VERSION 5.7 ;
  NOWIREEXTENSIONATPIN ON ;
  DIVIDERCHAR "/" ;
  BUSBITCHARS "[]" ;
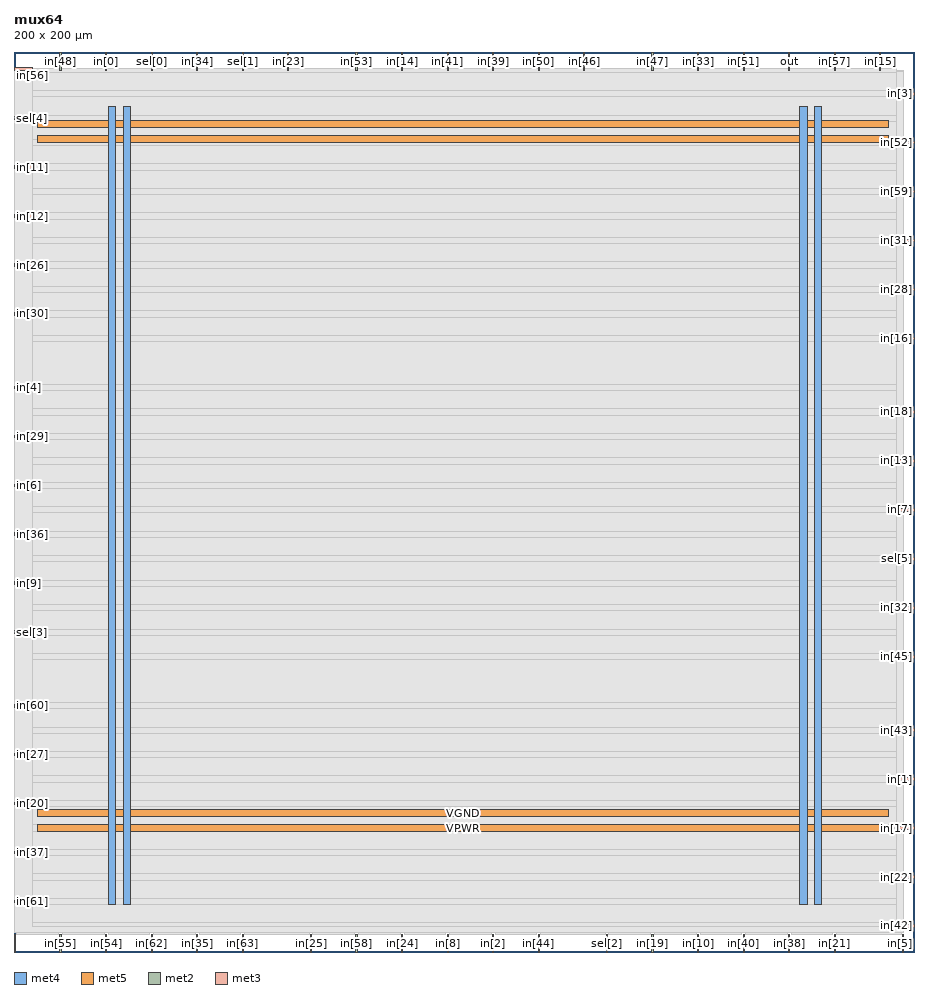
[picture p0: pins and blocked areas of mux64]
MACRO mux64
  CLASS BLOCK ;
  FOREIGN mux64 ;
  ORIGIN 0.000 0.000 ;
  SIZE 200.000 BY 200.000 ;
  PIN VGND
    DIRECTION INOUT ;
    USE GROUND ;
    PORT
      LAYER met4 ;
        RECT 24.340 10.640 25.940 187.920 ;
    END
    PORT
      LAYER met4 ;
        RECT 177.940 10.640 179.540 187.920 ;
    END
    PORT
      LAYER met5 ;
        RECT 5.280 30.030 194.360 31.630 ;
    END
    PORT
      LAYER met5 ;
        RECT 5.280 183.210 194.360 184.810 ;
    END
  END VGND
  PIN VPWR
    DIRECTION INOUT ;
    USE POWER ;
    PORT
      LAYER met4 ;
        RECT 21.040 10.640 22.640 187.920 ;
    END
    PORT
      LAYER met4 ;
        RECT 174.640 10.640 176.240 187.920 ;
    END
    PORT
      LAYER met5 ;
        RECT 5.280 26.730 194.360 28.330 ;
    END
    PORT
      LAYER met5 ;
        RECT 5.280 179.910 194.360 181.510 ;
    END
  END VPWR
  PIN in[0]
    DIRECTION INPUT ;
    USE SIGNAL ;
    ANTENNAGATEAREA 0.126000 ;
    PORT
      LAYER met2 ;
        RECT 20.330 196.000 20.610 200.000 ;
    END
  END in[0]
  PIN in[10]
    DIRECTION INPUT ;
    USE SIGNAL ;
    ANTENNAGATEAREA 0.196500 ;
    PORT
      LAYER met2 ;
        RECT 151.890 0.000 152.170 4.000 ;
    END
  END in[10]
  PIN in[11]
    DIRECTION INPUT ;
    USE SIGNAL ;
    ANTENNAGATEAREA 0.126000 ;
    PORT
      LAYER met3 ;
        RECT 0.000 174.120 4.000 174.720 ;
    END
  END in[11]
  PIN in[12]
    DIRECTION INPUT ;
    USE SIGNAL ;
    ANTENNAGATEAREA 0.196500 ;
    PORT
      LAYER met3 ;
        RECT 0.000 163.240 4.000 163.840 ;
    END
  END in[12]
  PIN in[13]
    DIRECTION INPUT ;
    USE SIGNAL ;
    ANTENNAGATEAREA 0.196500 ;
    PORT
      LAYER met3 ;
        RECT 196.000 108.840 200.000 109.440 ;
    END
  END in[13]
  PIN in[14]
    DIRECTION INPUT ;
    USE SIGNAL ;
    ANTENNAGATEAREA 0.196500 ;
    PORT
      LAYER met2 ;
        RECT 86.110 196.000 86.390 200.000 ;
    END
  END in[14]
  PIN in[15]
    DIRECTION INPUT ;
    USE SIGNAL ;
    ANTENNAGATEAREA 0.196500 ;
    PORT
      LAYER met2 ;
        RECT 192.370 196.000 192.650 200.000 ;
    END
  END in[15]
  PIN in[16]
    DIRECTION INPUT ;
    USE SIGNAL ;
    ANTENNAGATEAREA 0.196500 ;
    PORT
      LAYER met3 ;
        RECT 196.000 136.040 200.000 136.640 ;
    END
  END in[16]
  PIN in[17]
    DIRECTION INPUT ;
    USE SIGNAL ;
    ANTENNAGATEAREA 0.196500 ;
    PORT
      LAYER met3 ;
        RECT 196.000 27.240 200.000 27.840 ;
    END
  END in[17]
  PIN in[18]
    DIRECTION INPUT ;
    USE SIGNAL ;
    ANTENNAGATEAREA 0.196500 ;
    PORT
      LAYER met3 ;
        RECT 196.000 119.720 200.000 120.320 ;
    END
  END in[18]
  PIN in[19]
    DIRECTION INPUT ;
    USE SIGNAL ;
    ANTENNAGATEAREA 0.196500 ;
    PORT
      LAYER met2 ;
        RECT 141.770 0.000 142.050 4.000 ;
    END
  END in[19]
  PIN in[1]
    DIRECTION INPUT ;
    USE SIGNAL ;
    ANTENNAGATEAREA 0.196500 ;
    PORT
      LAYER met3 ;
        RECT 196.000 38.120 200.000 38.720 ;
    END
  END in[1]
  PIN in[20]
    DIRECTION INPUT ;
    USE SIGNAL ;
    ANTENNAGATEAREA 0.196500 ;
    PORT
      LAYER met3 ;
        RECT 0.000 32.680 4.000 33.280 ;
    END
  END in[20]
  PIN in[21]
    DIRECTION INPUT ;
    USE SIGNAL ;
    ANTENNAGATEAREA 0.196500 ;
    PORT
      LAYER met2 ;
        RECT 182.250 0.000 182.530 4.000 ;
    END
  END in[21]
  PIN in[22]
    DIRECTION INPUT ;
    USE SIGNAL ;
    ANTENNAGATEAREA 0.196500 ;
    PORT
      LAYER met3 ;
        RECT 196.000 16.360 200.000 16.960 ;
    END
  END in[22]
  PIN in[23]
    DIRECTION INPUT ;
    USE SIGNAL ;
    ANTENNAGATEAREA 0.126000 ;
    PORT
      LAYER met2 ;
        RECT 60.810 196.000 61.090 200.000 ;
    END
  END in[23]
  PIN in[24]
    DIRECTION INPUT ;
    USE SIGNAL ;
    ANTENNAGATEAREA 0.196500 ;
    PORT
      LAYER met2 ;
        RECT 86.110 0.000 86.390 4.000 ;
    END
  END in[24]
  PIN in[25]
    DIRECTION INPUT ;
    USE SIGNAL ;
    ANTENNAGATEAREA 0.196500 ;
    PORT
      LAYER met2 ;
        RECT 65.870 0.000 66.150 4.000 ;
    END
  END in[25]
  PIN in[26]
    DIRECTION INPUT ;
    USE SIGNAL ;
    ANTENNAGATEAREA 0.196500 ;
    PORT
      LAYER met3 ;
        RECT 0.000 152.360 4.000 152.960 ;
    END
  END in[26]
  PIN in[27]
    DIRECTION INPUT ;
    USE SIGNAL ;
    ANTENNAGATEAREA 0.196500 ;
    PORT
      LAYER met3 ;
        RECT 0.000 43.560 4.000 44.160 ;
    END
  END in[27]
  PIN in[28]
    DIRECTION INPUT ;
    USE SIGNAL ;
    ANTENNAGATEAREA 0.196500 ;
    PORT
      LAYER met3 ;
        RECT 196.000 146.920 200.000 147.520 ;
    END
  END in[28]
  PIN in[29]
    DIRECTION INPUT ;
    USE SIGNAL ;
    ANTENNAGATEAREA 0.196500 ;
    PORT
      LAYER met3 ;
        RECT 0.000 114.280 4.000 114.880 ;
    END
  END in[29]
  PIN in[2]
    DIRECTION INPUT ;
    USE SIGNAL ;
    ANTENNAGATEAREA 0.196500 ;
    PORT
      LAYER met2 ;
        RECT 106.350 0.000 106.630 4.000 ;
    END
  END in[2]
  PIN in[30]
    DIRECTION INPUT ;
    USE SIGNAL ;
    ANTENNAGATEAREA 0.196500 ;
    PORT
      LAYER met3 ;
        RECT 0.000 141.480 4.000 142.080 ;
    END
  END in[30]
  PIN in[31]
    DIRECTION INPUT ;
    USE SIGNAL ;
    ANTENNAGATEAREA 0.126000 ;
    PORT
      LAYER met3 ;
        RECT 196.000 157.800 200.000 158.400 ;
    END
  END in[31]
  PIN in[32]
    DIRECTION INPUT ;
    USE SIGNAL ;
    ANTENNAGATEAREA 0.196500 ;
    PORT
      LAYER met3 ;
        RECT 196.000 76.200 200.000 76.800 ;
    END
  END in[32]
  PIN in[33]
    DIRECTION INPUT ;
    USE SIGNAL ;
    ANTENNAGATEAREA 0.196500 ;
    PORT
      LAYER met2 ;
        RECT 151.890 196.000 152.170 200.000 ;
    END
  END in[33]
  PIN in[34]
    DIRECTION INPUT ;
    USE SIGNAL ;
    ANTENNAGATEAREA 0.196500 ;
    PORT
      LAYER met2 ;
        RECT 40.570 196.000 40.850 200.000 ;
    END
  END in[34]
  PIN in[35]
    DIRECTION INPUT ;
    USE SIGNAL ;
    ANTENNAGATEAREA 0.196500 ;
    PORT
      LAYER met2 ;
        RECT 40.570 0.000 40.850 4.000 ;
    END
  END in[35]
  PIN in[36]
    DIRECTION INPUT ;
    USE SIGNAL ;
    ANTENNAGATEAREA 0.196500 ;
    PORT
      LAYER met3 ;
        RECT 0.000 92.520 4.000 93.120 ;
    END
  END in[36]
  PIN in[37]
    DIRECTION INPUT ;
    USE SIGNAL ;
    ANTENNAGATEAREA 0.196500 ;
    PORT
      LAYER met3 ;
        RECT 0.000 21.800 4.000 22.400 ;
    END
  END in[37]
  PIN in[38]
    DIRECTION INPUT ;
    USE SIGNAL ;
    ANTENNAGATEAREA 0.196500 ;
    PORT
      LAYER met2 ;
        RECT 172.130 0.000 172.410 4.000 ;
    END
  END in[38]
  PIN in[39]
    DIRECTION INPUT ;
    USE SIGNAL ;
    ANTENNAGATEAREA 0.196500 ;
    PORT
      LAYER met2 ;
        RECT 106.350 196.000 106.630 200.000 ;
    END
  END in[39]
  PIN in[3]
    DIRECTION INPUT ;
    USE SIGNAL ;
    ANTENNAGATEAREA 0.196500 ;
    PORT
      LAYER met3 ;
        RECT 196.000 190.440 200.000 191.040 ;
    END
  END in[3]
  PIN in[40]
    DIRECTION INPUT ;
    USE SIGNAL ;
    ANTENNAGATEAREA 0.196500 ;
    PORT
      LAYER met2 ;
        RECT 162.010 0.000 162.290 4.000 ;
    END
  END in[40]
  PIN in[41]
    DIRECTION INPUT ;
    USE SIGNAL ;
    ANTENNAGATEAREA 0.196500 ;
    PORT
      LAYER met2 ;
        RECT 96.230 196.000 96.510 200.000 ;
    END
  END in[41]
  PIN in[42]
    DIRECTION INPUT ;
    USE SIGNAL ;
    ANTENNAGATEAREA 0.196500 ;
    PORT
      LAYER met3 ;
        RECT 196.000 5.480 200.000 6.080 ;
    END
  END in[42]
  PIN in[43]
    DIRECTION INPUT ;
    USE SIGNAL ;
    ANTENNAGATEAREA 0.196500 ;
    PORT
      LAYER met3 ;
        RECT 196.000 49.000 200.000 49.600 ;
    END
  END in[43]
  PIN in[44]
    DIRECTION INPUT ;
    USE SIGNAL ;
    ANTENNAGATEAREA 0.196500 ;
    PORT
      LAYER met2 ;
        RECT 116.470 0.000 116.750 4.000 ;
    END
  END in[44]
  PIN in[45]
    DIRECTION INPUT ;
    USE SIGNAL ;
    ANTENNAGATEAREA 0.196500 ;
    PORT
      LAYER met3 ;
        RECT 196.000 65.320 200.000 65.920 ;
    END
  END in[45]
  PIN in[46]
    DIRECTION INPUT ;
    USE SIGNAL ;
    ANTENNAGATEAREA 0.196500 ;
    PORT
      LAYER met2 ;
        RECT 126.590 196.000 126.870 200.000 ;
    END
  END in[46]
  PIN in[47]
    DIRECTION INPUT ;
    USE SIGNAL ;
    ANTENNAGATEAREA 0.196500 ;
    PORT
      LAYER met2 ;
        RECT 141.770 196.000 142.050 200.000 ;
    END
  END in[47]
  PIN in[48]
    DIRECTION INPUT ;
    USE SIGNAL ;
    ANTENNAGATEAREA 0.196500 ;
    PORT
      LAYER met2 ;
        RECT 10.210 196.000 10.490 200.000 ;
    END
  END in[48]
  PIN in[49]
    DIRECTION INPUT ;
    USE SIGNAL ;
    ANTENNAGATEAREA 0.196500 ;
    PORT
      LAYER met2 ;
        RECT 0.090 0.000 0.370 4.000 ;
    END
  END in[49]
  PIN in[4]
    DIRECTION INPUT ;
    USE SIGNAL ;
    ANTENNAGATEAREA 0.196500 ;
    PORT
      LAYER met3 ;
        RECT 0.000 125.160 4.000 125.760 ;
    END
  END in[4]
  PIN in[50]
    DIRECTION INPUT ;
    USE SIGNAL ;
    ANTENNAGATEAREA 0.196500 ;
    PORT
      LAYER met2 ;
        RECT 116.470 196.000 116.750 200.000 ;
    END
  END in[50]
  PIN in[51]
    DIRECTION INPUT ;
    USE SIGNAL ;
    ANTENNAGATEAREA 0.196500 ;
    PORT
      LAYER met2 ;
        RECT 162.010 196.000 162.290 200.000 ;
    END
  END in[51]
  PIN in[52]
    DIRECTION INPUT ;
    USE SIGNAL ;
    ANTENNAGATEAREA 0.196500 ;
    PORT
      LAYER met3 ;
        RECT 196.000 179.560 200.000 180.160 ;
    END
  END in[52]
  PIN in[53]
    DIRECTION INPUT ;
    USE SIGNAL ;
    ANTENNAGATEAREA 0.196500 ;
    PORT
      LAYER met2 ;
        RECT 75.990 196.000 76.270 200.000 ;
    END
  END in[53]
  PIN in[54]
    DIRECTION INPUT ;
    USE SIGNAL ;
    ANTENNAGATEAREA 0.196500 ;
    PORT
      LAYER met2 ;
        RECT 20.330 0.000 20.610 4.000 ;
    END
  END in[54]
  PIN in[55]
    DIRECTION INPUT ;
    USE SIGNAL ;
    ANTENNAGATEAREA 0.196500 ;
    PORT
      LAYER met2 ;
        RECT 10.210 0.000 10.490 4.000 ;
    END
  END in[55]
  PIN in[56]
    DIRECTION INPUT ;
    USE SIGNAL ;
    ANTENNAGATEAREA 0.196500 ;
    PORT
      LAYER met3 ;
        RECT 0.000 195.880 4.000 196.480 ;
    END
  END in[56]
  PIN in[57]
    DIRECTION INPUT ;
    USE SIGNAL ;
    ANTENNAGATEAREA 0.196500 ;
    PORT
      LAYER met2 ;
        RECT 182.250 196.000 182.530 200.000 ;
    END
  END in[57]
  PIN in[58]
    DIRECTION INPUT ;
    USE SIGNAL ;
    ANTENNAGATEAREA 0.196500 ;
    PORT
      LAYER met2 ;
        RECT 75.990 0.000 76.270 4.000 ;
    END
  END in[58]
  PIN in[59]
    DIRECTION INPUT ;
    USE SIGNAL ;
    ANTENNAGATEAREA 0.126000 ;
    PORT
      LAYER met3 ;
        RECT 196.000 168.680 200.000 169.280 ;
    END
  END in[59]
  PIN in[5]
    DIRECTION INPUT ;
    USE SIGNAL ;
    ANTENNAGATEAREA 0.126000 ;
    PORT
      LAYER met2 ;
        RECT 197.430 0.000 197.710 4.000 ;
    END
  END in[5]
  PIN in[60]
    DIRECTION INPUT ;
    USE SIGNAL ;
    ANTENNAGATEAREA 0.196500 ;
    PORT
      LAYER met3 ;
        RECT 0.000 54.440 4.000 55.040 ;
    END
  END in[60]
  PIN in[61]
    DIRECTION INPUT ;
    USE SIGNAL ;
    ANTENNAGATEAREA 0.196500 ;
    PORT
      LAYER met3 ;
        RECT 0.000 10.920 4.000 11.520 ;
    END
  END in[61]
  PIN in[62]
    DIRECTION INPUT ;
    USE SIGNAL ;
    ANTENNAGATEAREA 0.196500 ;
    PORT
      LAYER met2 ;
        RECT 30.450 0.000 30.730 4.000 ;
    END
  END in[62]
  PIN in[63]
    DIRECTION INPUT ;
    USE SIGNAL ;
    ANTENNAGATEAREA 0.196500 ;
    PORT
      LAYER met2 ;
        RECT 50.690 0.000 50.970 4.000 ;
    END
  END in[63]
  PIN in[6]
    DIRECTION INPUT ;
    USE SIGNAL ;
    ANTENNAGATEAREA 0.196500 ;
    PORT
      LAYER met3 ;
        RECT 0.000 103.400 4.000 104.000 ;
    END
  END in[6]
  PIN in[7]
    DIRECTION INPUT ;
    USE SIGNAL ;
    ANTENNAGATEAREA 0.196500 ;
    PORT
      LAYER met3 ;
        RECT 196.000 97.960 200.000 98.560 ;
    END
  END in[7]
  PIN in[8]
    DIRECTION INPUT ;
    USE SIGNAL ;
    ANTENNAGATEAREA 0.196500 ;
    PORT
      LAYER met2 ;
        RECT 96.230 0.000 96.510 4.000 ;
    END
  END in[8]
  PIN in[9]
    DIRECTION INPUT ;
    USE SIGNAL ;
    ANTENNAGATEAREA 0.196500 ;
    PORT
      LAYER met3 ;
        RECT 0.000 81.640 4.000 82.240 ;
    END
  END in[9]
  PIN out
    DIRECTION OUTPUT TRISTATE ;
    USE SIGNAL ;
    ANTENNADIFFAREA 0.795200 ;
    PORT
      LAYER met2 ;
        RECT 172.130 196.000 172.410 200.000 ;
    END
  END out
  PIN sel[0]
    DIRECTION INPUT ;
    USE SIGNAL ;
    ANTENNAGATEAREA 0.159000 ;
    PORT
      LAYER met2 ;
        RECT 30.450 196.000 30.730 200.000 ;
    END
  END sel[0]
  PIN sel[1]
    DIRECTION INPUT ;
    USE SIGNAL ;
    ANTENNAGATEAREA 0.247500 ;
    PORT
      LAYER met2 ;
        RECT 50.690 196.000 50.970 200.000 ;
    END
  END sel[1]
  PIN sel[2]
    DIRECTION INPUT ;
    USE SIGNAL ;
    ANTENNAGATEAREA 0.213000 ;
    PORT
      LAYER met2 ;
        RECT 131.650 0.000 131.930 4.000 ;
    END
  END sel[2]
  PIN sel[3]
    DIRECTION INPUT ;
    USE SIGNAL ;
    ANTENNAGATEAREA 0.159000 ;
    PORT
      LAYER met3 ;
        RECT 0.000 70.760 4.000 71.360 ;
    END
  END sel[3]
  PIN sel[4]
    DIRECTION INPUT ;
    USE SIGNAL ;
    ANTENNAGATEAREA 0.159000 ;
    PORT
      LAYER met3 ;
        RECT 0.000 185.000 4.000 185.600 ;
    END
  END sel[4]
  PIN sel[5]
    DIRECTION INPUT ;
    USE SIGNAL ;
    ANTENNAGATEAREA 0.213000 ;
    PORT
      LAYER met3 ;
        RECT 196.000 87.080 200.000 87.680 ;
    END
  END sel[5]
  OBS
      LAYER li1 ;
        RECT 5.520 10.795 194.120 187.765 ;
      LAYER met1 ;
        RECT 0.070 9.560 197.730 187.920 ;
      LAYER met2 ;
        RECT 0.100 195.720 9.930 196.000 ;
        RECT 10.770 195.720 20.050 196.000 ;
        RECT 20.890 195.720 30.170 196.000 ;
        RECT 31.010 195.720 40.290 196.000 ;
        RECT 41.130 195.720 50.410 196.000 ;
        RECT 51.250 195.720 60.530 196.000 ;
        RECT 61.370 195.720 75.710 196.000 ;
        RECT 76.550 195.720 85.830 196.000 ;
        RECT 86.670 195.720 95.950 196.000 ;
        RECT 96.790 195.720 106.070 196.000 ;
        RECT 106.910 195.720 116.190 196.000 ;
        RECT 117.030 195.720 126.310 196.000 ;
        RECT 127.150 195.720 141.490 196.000 ;
        RECT 142.330 195.720 151.610 196.000 ;
        RECT 152.450 195.720 161.730 196.000 ;
        RECT 162.570 195.720 171.850 196.000 ;
        RECT 172.690 195.720 181.970 196.000 ;
        RECT 182.810 195.720 192.090 196.000 ;
        RECT 192.930 195.720 197.700 196.000 ;
        RECT 0.100 4.280 197.700 195.720 ;
        RECT 0.650 4.000 9.930 4.280 ;
        RECT 10.770 4.000 20.050 4.280 ;
        RECT 20.890 4.000 30.170 4.280 ;
        RECT 31.010 4.000 40.290 4.280 ;
        RECT 41.130 4.000 50.410 4.280 ;
        RECT 51.250 4.000 65.590 4.280 ;
        RECT 66.430 4.000 75.710 4.280 ;
        RECT 76.550 4.000 85.830 4.280 ;
        RECT 86.670 4.000 95.950 4.280 ;
        RECT 96.790 4.000 106.070 4.280 ;
        RECT 106.910 4.000 116.190 4.280 ;
        RECT 117.030 4.000 131.370 4.280 ;
        RECT 132.210 4.000 141.490 4.280 ;
        RECT 142.330 4.000 151.610 4.280 ;
        RECT 152.450 4.000 161.730 4.280 ;
        RECT 162.570 4.000 171.850 4.280 ;
        RECT 172.690 4.000 181.970 4.280 ;
        RECT 182.810 4.000 197.150 4.280 ;
      LAYER met3 ;
        RECT 4.400 195.480 196.000 196.330 ;
        RECT 4.000 191.440 196.000 195.480 ;
        RECT 4.000 190.040 195.600 191.440 ;
        RECT 4.000 186.000 196.000 190.040 ;
        RECT 4.400 184.600 196.000 186.000 ;
        RECT 4.000 180.560 196.000 184.600 ;
        RECT 4.000 179.160 195.600 180.560 ;
        RECT 4.000 175.120 196.000 179.160 ;
        RECT 4.400 173.720 196.000 175.120 ;
        RECT 4.000 169.680 196.000 173.720 ;
        RECT 4.000 168.280 195.600 169.680 ;
        RECT 4.000 164.240 196.000 168.280 ;
        RECT 4.400 162.840 196.000 164.240 ;
        RECT 4.000 158.800 196.000 162.840 ;
        RECT 4.000 157.400 195.600 158.800 ;
        RECT 4.000 153.360 196.000 157.400 ;
        RECT 4.400 151.960 196.000 153.360 ;
        RECT 4.000 147.920 196.000 151.960 ;
        RECT 4.000 146.520 195.600 147.920 ;
        RECT 4.000 142.480 196.000 146.520 ;
        RECT 4.400 141.080 196.000 142.480 ;
        RECT 4.000 137.040 196.000 141.080 ;
        RECT 4.000 135.640 195.600 137.040 ;
        RECT 4.000 126.160 196.000 135.640 ;
        RECT 4.400 124.760 196.000 126.160 ;
        RECT 4.000 120.720 196.000 124.760 ;
        RECT 4.000 119.320 195.600 120.720 ;
        RECT 4.000 115.280 196.000 119.320 ;
        RECT 4.400 113.880 196.000 115.280 ;
        RECT 4.000 109.840 196.000 113.880 ;
        RECT 4.000 108.440 195.600 109.840 ;
        RECT 4.000 104.400 196.000 108.440 ;
        RECT 4.400 103.000 196.000 104.400 ;
        RECT 4.000 98.960 196.000 103.000 ;
        RECT 4.000 97.560 195.600 98.960 ;
        RECT 4.000 93.520 196.000 97.560 ;
        RECT 4.400 92.120 196.000 93.520 ;
        RECT 4.000 88.080 196.000 92.120 ;
        RECT 4.000 86.680 195.600 88.080 ;
        RECT 4.000 82.640 196.000 86.680 ;
        RECT 4.400 81.240 196.000 82.640 ;
        RECT 4.000 77.200 196.000 81.240 ;
        RECT 4.000 75.800 195.600 77.200 ;
        RECT 4.000 71.760 196.000 75.800 ;
        RECT 4.400 70.360 196.000 71.760 ;
        RECT 4.000 66.320 196.000 70.360 ;
        RECT 4.000 64.920 195.600 66.320 ;
        RECT 4.000 55.440 196.000 64.920 ;
        RECT 4.400 54.040 196.000 55.440 ;
        RECT 4.000 50.000 196.000 54.040 ;
        RECT 4.000 48.600 195.600 50.000 ;
        RECT 4.000 44.560 196.000 48.600 ;
        RECT 4.400 43.160 196.000 44.560 ;
        RECT 4.000 39.120 196.000 43.160 ;
        RECT 4.000 37.720 195.600 39.120 ;
        RECT 4.000 33.680 196.000 37.720 ;
        RECT 4.400 32.280 196.000 33.680 ;
        RECT 4.000 28.240 196.000 32.280 ;
        RECT 4.000 26.840 195.600 28.240 ;
        RECT 4.000 22.800 196.000 26.840 ;
        RECT 4.400 21.400 196.000 22.800 ;
        RECT 4.000 17.360 196.000 21.400 ;
        RECT 4.000 15.960 195.600 17.360 ;
        RECT 4.000 11.920 196.000 15.960 ;
        RECT 4.400 10.520 196.000 11.920 ;
        RECT 4.000 6.480 196.000 10.520 ;
        RECT 4.000 5.615 195.600 6.480 ;
  END
END mux64
END LIBRARY

